VERSION 5.7 ;
  NOWIREEXTENSIONATPIN ON ;
  DIVIDERCHAR "/" ;
  BUSBITCHARS "[]" ;
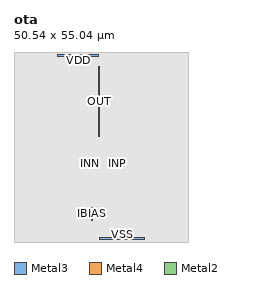
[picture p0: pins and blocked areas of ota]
MACRO ota
  CLASS BLOCK ;
  FOREIGN ota ;
  ORIGIN 25.260 3.940 ;
  SIZE 50.540 BY 55.040 ;
  PIN IBIAS
    ANTENNAGATEAREA 52.000000 ;
    ANTENNADIFFAREA 1.200000 ;
    PORT
      LAYER Metal3 ;
        RECT -2.680 2.300 -2.400 6.100 ;
    END
  END IBIAS
  PIN OUT
    ANTENNADIFFAREA 12.000000 ;
    PORT
      LAYER Metal4 ;
        RECT -0.640 26.500 -0.360 46.900 ;
    END
  END OUT
  PIN INN
    ANTENNAGATEAREA 18.000000 ;
    PORT
      LAYER Metal2 ;
        RECT -3.270 18.550 -2.990 18.830 ;
    END
  END INN
  PIN INP
    ANTENNAGATEAREA 18.000000 ;
    PORT
      LAYER Metal2 ;
        RECT 4.590 18.550 4.870 18.830 ;
    END
  END INP
  PIN VSS
    USE GROUND ;
    PORT
      LAYER Metal3 ;
        RECT -0.360 -3.220 12.620 -2.660 ;
    END
  END VSS
  PIN VDD
    USE POWER ;
    PORT
      LAYER Metal3 ;
        RECT -12.600 49.820 -0.640 50.380 ;
    END
  END VDD
  OBS
      LAYER Nwell ;
        RECT -22.040 0.000 22.040 46.770 ;
      LAYER Metal1 ;
        RECT -21.810 0.210 21.810 46.560 ;
      LAYER Metal2 ;
        RECT -22.170 19.130 22.190 46.560 ;
        RECT -22.170 18.250 -3.570 19.130 ;
        RECT -2.690 18.250 4.290 19.130 ;
        RECT 5.170 18.250 22.190 19.130 ;
        RECT -22.170 0.210 22.190 18.250 ;
      LAYER Metal3 ;
        RECT -25.260 49.520 -12.900 50.380 ;
        RECT -0.340 49.520 25.280 50.380 ;
        RECT -25.260 6.400 25.280 49.520 ;
        RECT -25.260 2.000 -2.980 6.400 ;
        RECT -2.100 2.000 25.280 6.400 ;
        RECT -25.260 -2.360 25.280 2.000 ;
        RECT -25.260 -2.660 -0.660 -2.360 ;
        RECT -25.260 -2.800 -0.360 -2.660 ;
        RECT -25.260 -3.080 -0.660 -2.800 ;
        RECT -25.260 -3.220 -0.360 -3.080 ;
        RECT 12.920 -3.220 25.280 -2.360 ;
      LAYER Metal4 ;
        RECT -25.230 47.200 25.250 50.350 ;
        RECT -25.230 26.200 -0.940 47.200 ;
        RECT -0.060 26.200 25.250 47.200 ;
        RECT -25.230 -3.190 25.250 26.200 ;
      LAYER Metal5 ;
        RECT -25.230 -3.940 25.250 51.100 ;
  END
END ota
END LIBRARY

